(* Logix 5000 AddOnInstructionDefinition export SHA512_SEQ; software revision 30.00; part 2 of 2 *)
(* tags used below, declared in another part *)
   Out_HASH : LINT[8];
   SEQCTRL_DN : BOOL;   // Complete
   SEQCTRL_STEP : INT;
   SEQCTRL_CMD : DINT;
   SEQCTRL_DONE : DINT;
   SEQCTRL_NEXT_STEP : INT;
   i : INT;
   HashBuffer_A : LINT;
   HashBuffer_B : LINT;
   HashBuffer_C : LINT;
   HashBuffer_D : LINT;
   HashBuffer_E : LINT;
   HashBuffer_F : LINT;
   HashBuffer_G : LINT;
   HashBuffer_H : LINT;
   HashBufferInput_A : LINT;
   HashBufferInput_B : LINT;
   HashBufferInput_C : LINT;
   HashBufferInput_D : LINT;
   HashBufferInput_E : LINT;
   HashBufferInput_F : LINT;
   HashBufferInput_G : LINT;
   HashBufferInput_H : LINT;
   M : INT;   // MESSAGE INCREMENTS
   t : INT;
   L_ADD : L_ADD;
   TOTAL_MSG_LENGTH_MINUS_16 : DINT;
   TEMP : DINT;
(* SHA512_SEQ, continued *)

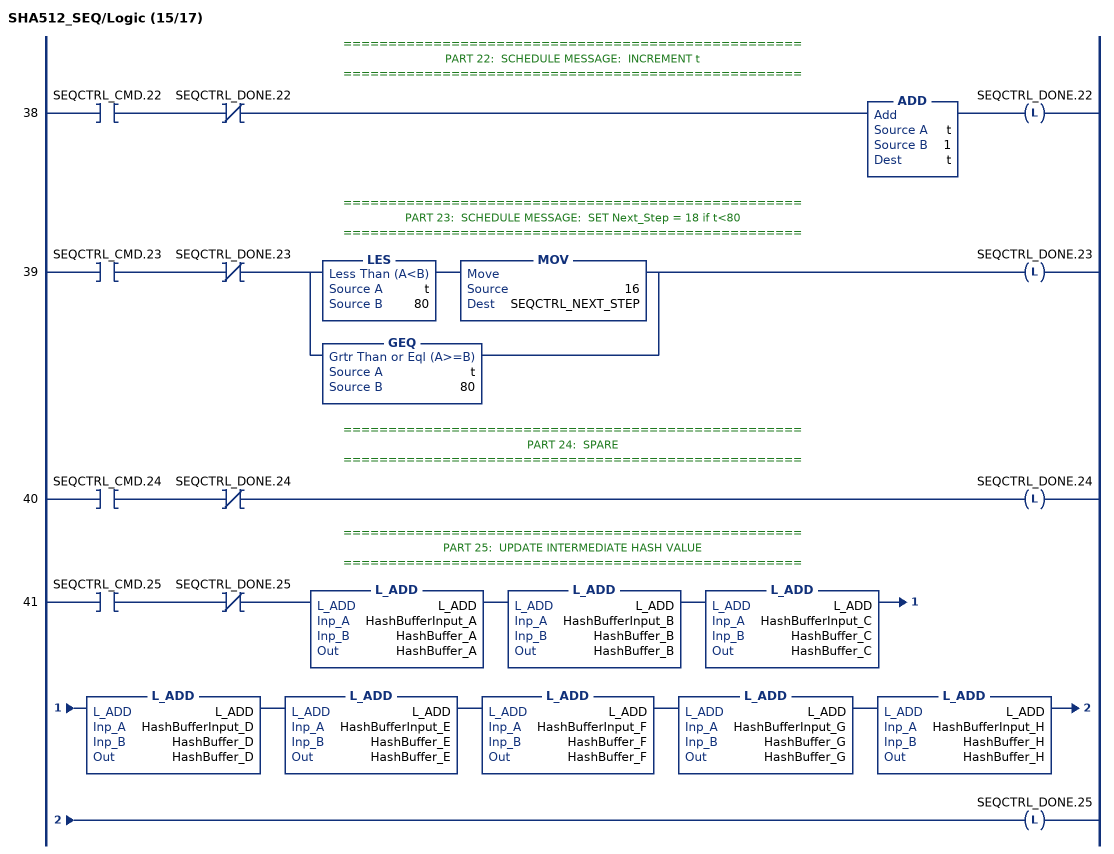
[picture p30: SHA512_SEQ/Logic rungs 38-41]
   // ===================================================
   // PART 22:  SCHEDULE MESSAGE:  INCREMENT t
   // ===================================================
   38: XIC(SEQCTRL_CMD.22)XIO(SEQCTRL_DONE.22)ADD(t,1,t)OTL(SEQCTRL_DONE.22);
   // ===================================================
   // PART 23:  SCHEDULE MESSAGE:  SET Next_Step = 18 if t<80
   // ===================================================
   39: XIC(SEQCTRL_CMD.23)XIO(SEQCTRL_DONE.23)[LES(t,80) MOV(16,SEQCTRL_NEXT_STEP) ,GEQ(t,80) ]OTL(SEQCTRL_DONE.23);
   // ===================================================
   // PART 24:  SPARE
   // ===================================================
   40: XIC(SEQCTRL_CMD.24)XIO(SEQCTRL_DONE.24)OTL(SEQCTRL_DONE.24);
   // ===================================================
   // PART 25:  UPDATE INTERMEDIATE HASH VALUE
   // ===================================================
   41: XIC(SEQCTRL_CMD.25)XIO(SEQCTRL_DONE.25)L_ADD(L_ADD,HashBufferInput_A,HashBuffer_A,HashBuffer_A)L_ADD(L_ADD,HashBufferInput_B,HashBuffer_B,HashBuffer_B)L_ADD(L_ADD,HashBufferInput_C,HashBuffer_C,HashBuffer_C)L_ADD(L_ADD,HashBufferInput_D,HashBuffer_D,HashBuffer_D)L_ADD(L_ADD,HashBufferInput_E,HashBuffer_E,HashBuffer_E)L_ADD(L_ADD,HashBufferInput_F,HashBuffer_F,HashBuffer_F)L_ADD(L_ADD,HashBufferInput_G,HashBuffer_G,HashBuffer_G)L_ADD(L_ADD,HashBufferInput_H,HashBuffer_H,HashBuffer_H)OTL(SEQCTRL_DONE.25);
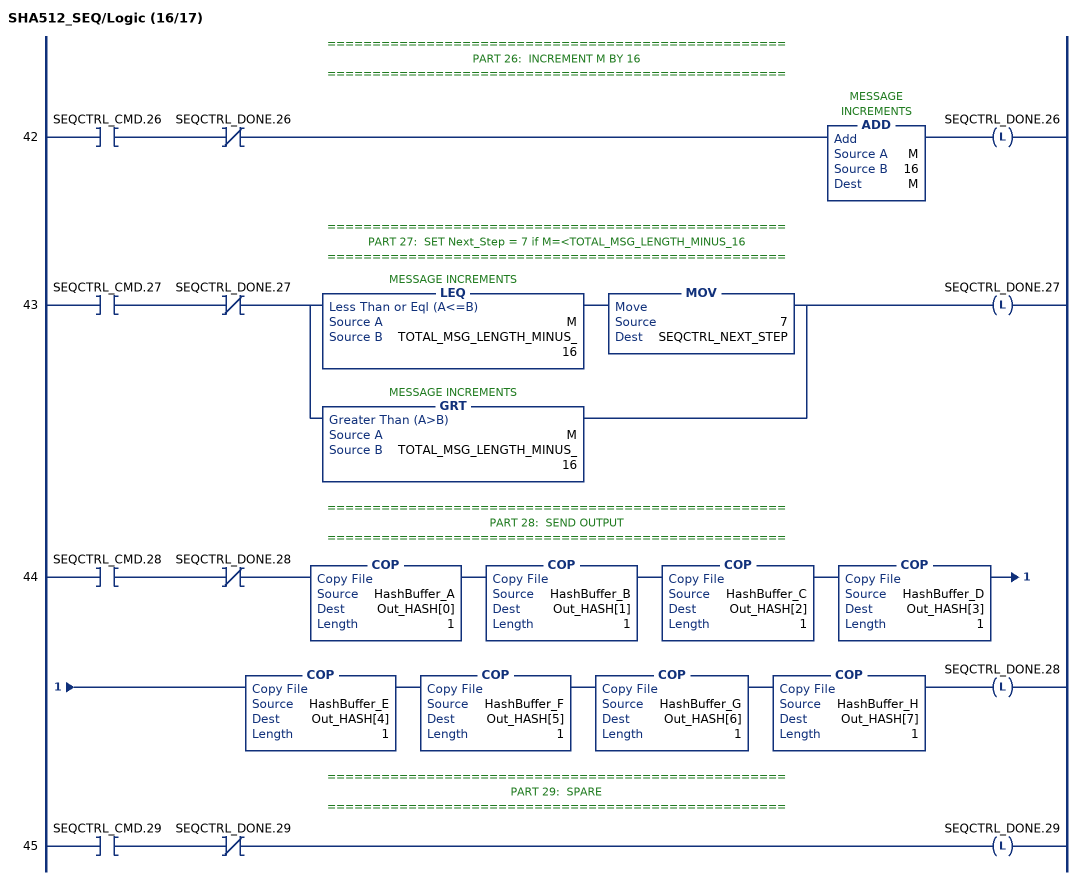
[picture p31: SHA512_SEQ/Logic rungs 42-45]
   // ===================================================
   // PART 26:  INCREMENT M BY 16
   // ===================================================
   42: XIC(SEQCTRL_CMD.26)XIO(SEQCTRL_DONE.26)ADD(M,16,M)OTL(SEQCTRL_DONE.26);
   // ===================================================
   // PART 27:  SET Next_Step = 7 if M=<TOTAL_MSG_LENGTH_MINUS_16
   // ===================================================
   43: XIC(SEQCTRL_CMD.27)XIO(SEQCTRL_DONE.27)[LEQ(M,TOTAL_MSG_LENGTH_MINUS_16) MOV(7,SEQCTRL_NEXT_STEP) ,GRT(M,TOTAL_MSG_LENGTH_MINUS_16) ]OTL(SEQCTRL_DONE.27);
   // ===================================================
   // PART 28:  SEND OUTPUT
   // ===================================================
   44: XIC(SEQCTRL_CMD.28)XIO(SEQCTRL_DONE.28)COP(HashBuffer_A,Out_HASH[0],1)COP(HashBuffer_B,Out_HASH[1],1)COP(HashBuffer_C,Out_HASH[2],1)COP(HashBuffer_D,Out_HASH[3],1)COP(HashBuffer_E,Out_HASH[4],1)COP(HashBuffer_F,Out_HASH[5],1)COP(HashBuffer_G,Out_HASH[6],1)COP(HashBuffer_H,Out_HASH[7],1)OTL(SEQCTRL_DONE.28);
   // ===================================================
   // PART 29:  SPARE
   // ===================================================
   45: XIC(SEQCTRL_CMD.29)XIO(SEQCTRL_DONE.29)OTL(SEQCTRL_DONE.29);
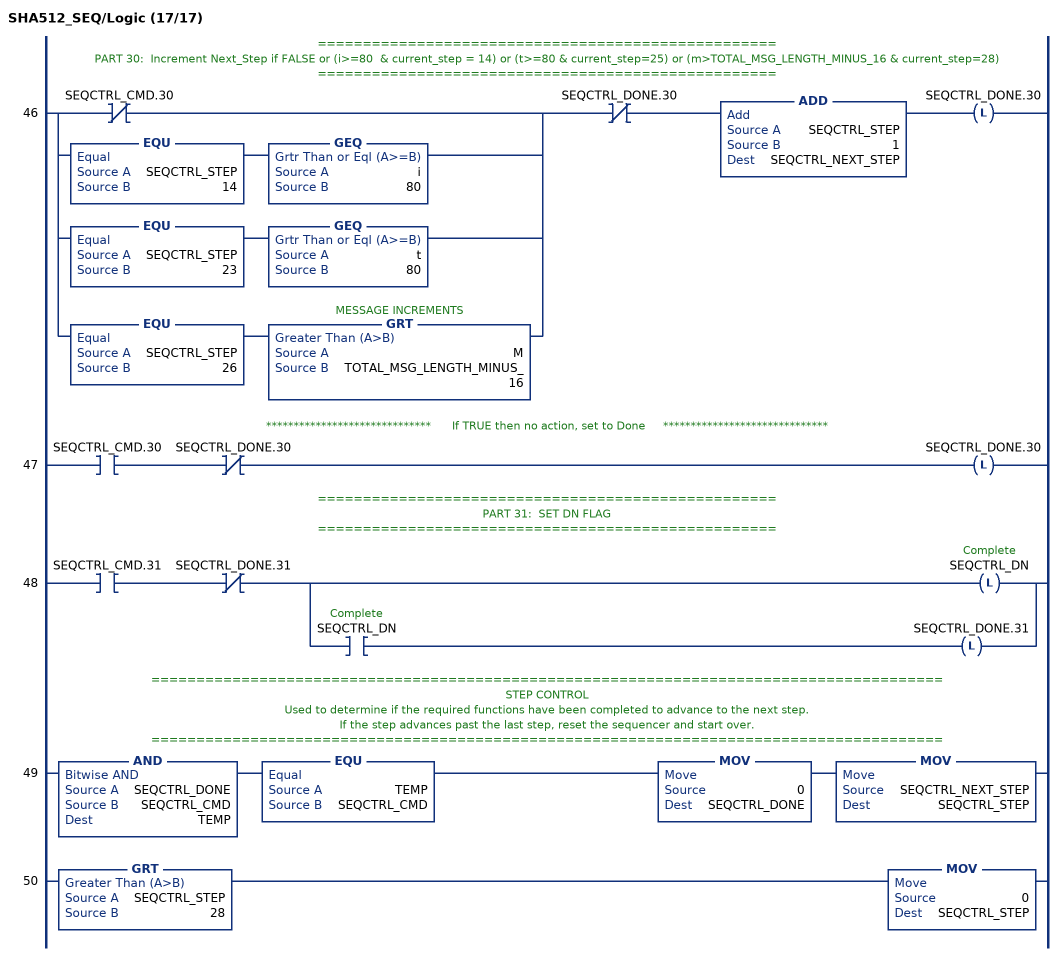
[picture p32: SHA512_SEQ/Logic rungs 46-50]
   // ===================================================
   // PART 30:  Increment Next_Step if FALSE or (i>=80  & current_step = 14) or (t>=80 & current_step=25) or (m>TOTAL_MSG_LENGTH_MINUS_16 & current_step=28)
   // ===================================================
   46: [XIO(SEQCTRL_CMD.30) ,EQU(SEQCTRL_STEP,14) GEQ(i,80) ,EQU(SEQCTRL_STEP,23) GEQ(t,80) ,EQU(SEQCTRL_STEP,26) GRT(M,TOTAL_MSG_LENGTH_MINUS_16) ]XIO(SEQCTRL_DONE.30)ADD(SEQCTRL_STEP,1,SEQCTRL_NEXT_STEP)OTL(SEQCTRL_DONE.30);
   // ******************************      If TRUE then no action, set to Done     ******************************
   47: XIC(SEQCTRL_CMD.30)XIO(SEQCTRL_DONE.30)OTL(SEQCTRL_DONE.30);
   // ===================================================
   // PART 31:  SET DN FLAG
   // ===================================================
   48: XIC(SEQCTRL_CMD.31)XIO(SEQCTRL_DONE.31)[OTL(SEQCTRL_DN) ,XIC(SEQCTRL_DN) OTL(SEQCTRL_DONE.31) ];
   // ========================================================================================
   // STEP CONTROL
   // Used to determine if the required functions have been completed to advance to the next step.
   // If the step advances past the last step, reset the sequencer and start over.
   // ========================================================================================
   49: AND(SEQCTRL_DONE,SEQCTRL_CMD,TEMP)EQU(TEMP,SEQCTRL_CMD)MOV(0,SEQCTRL_DONE)MOV(SEQCTRL_NEXT_STEP,SEQCTRL_STEP);
   50: GRT(SEQCTRL_STEP,28)MOV(0,SEQCTRL_STEP);
END_ROUTINE
END_ADD_ON_INSTRUCTION
